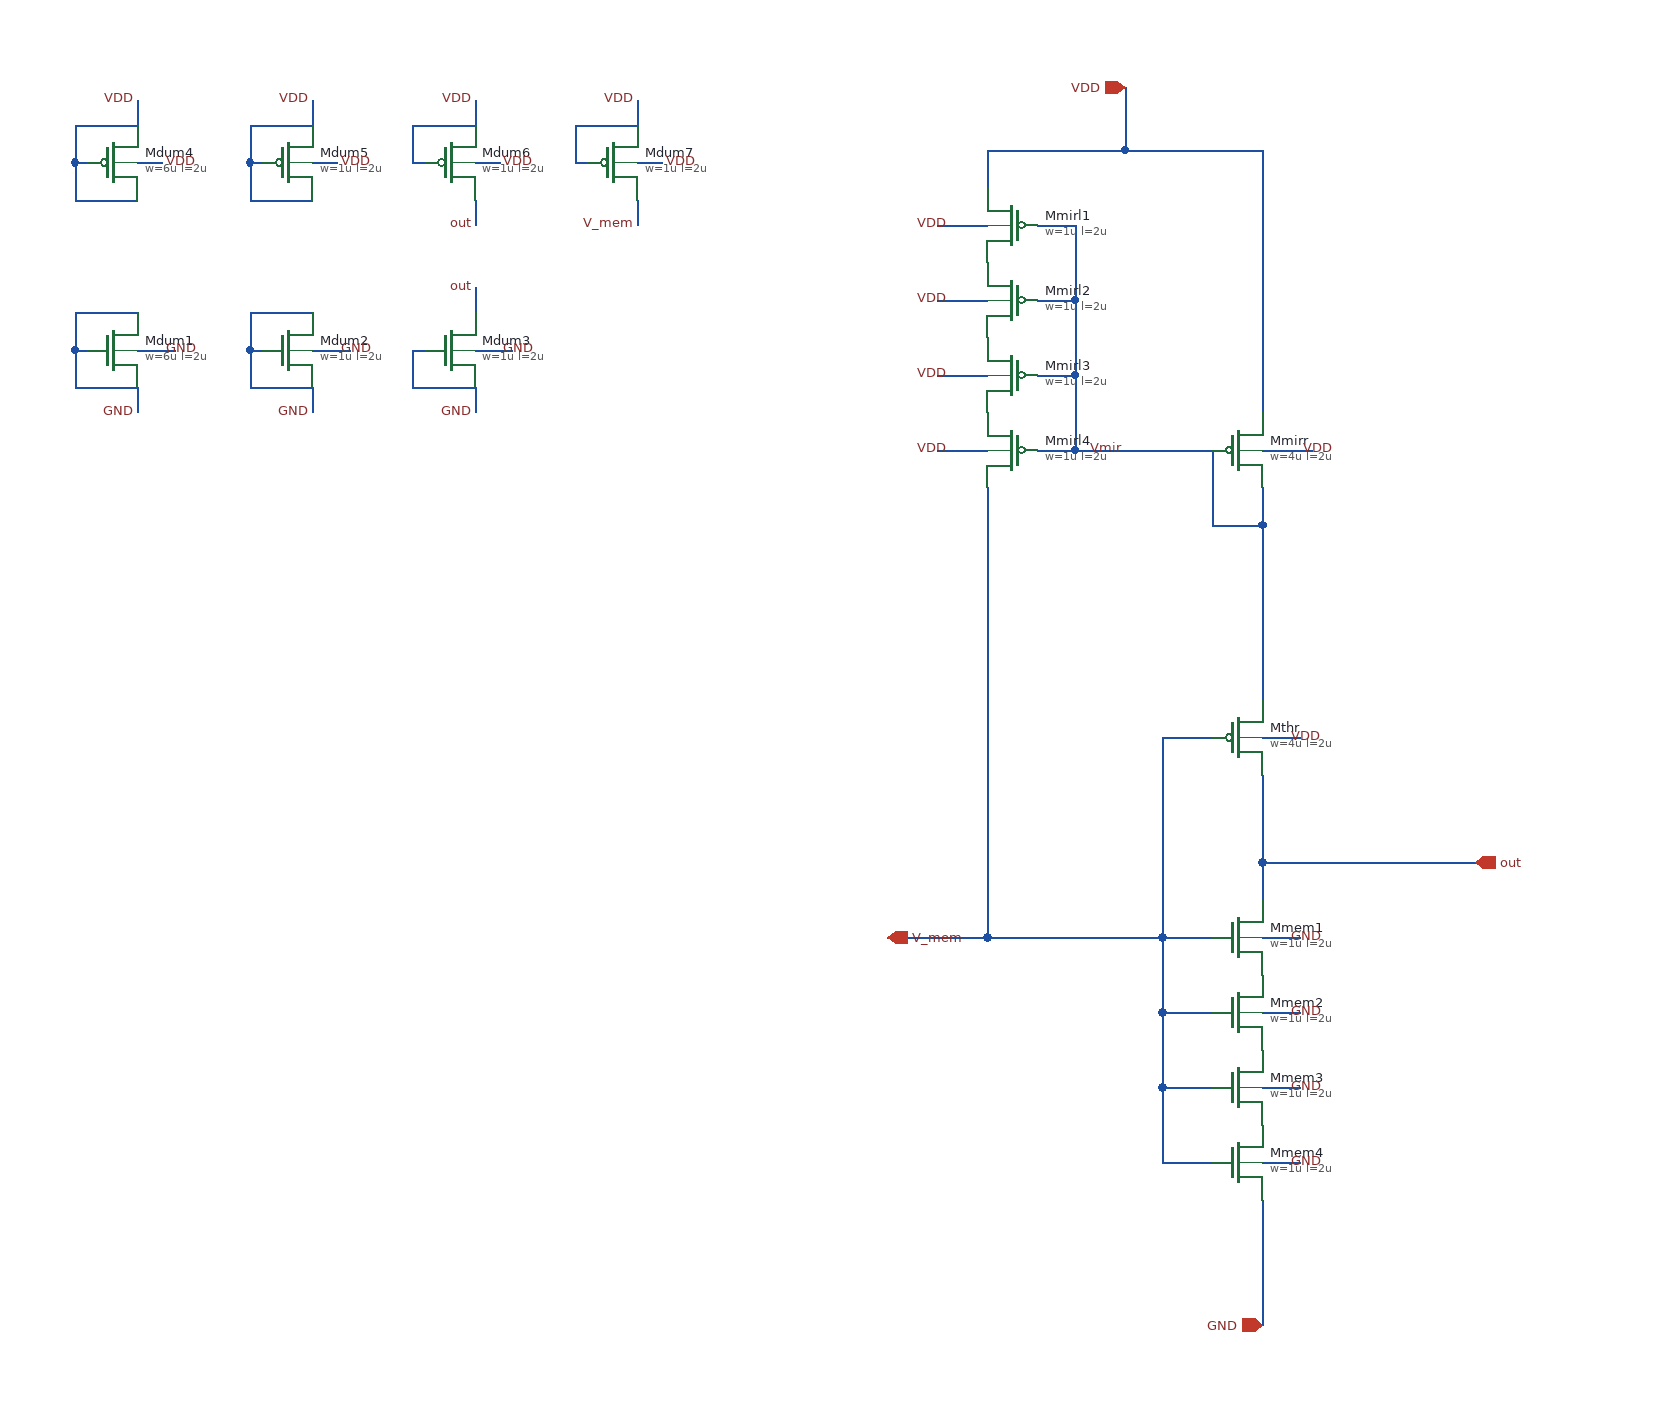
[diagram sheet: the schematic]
v {xschem version=3.4.8RC file_version=1.3}
G {}
K {}
V {}
S {}
F {}
E {}
N -1470 -1430 -1470 -1400 {lab=out}
N -1550 -1370 -1510 -1370 {lab=V_mem}
N -1470 -1500 -1470 -1430 {lab=out}
N -1550 -1530 -1510 -1530 {lab=V_mem}
N -1550 -1530 -1550 -1370 {lab=V_mem}
N -1510 -1760 -1510 -1700 {lab=Vmir}
N -1510 -1700 -1470 -1700 {lab=Vmir}
N -1470 -1730 -1470 -1700 {lab=Vmir}
N -1620 -1760 -1510 -1760 {lab=Vmir}
N -1470 -1430 -1300 -1430 {lab=out}
N -1580 -2050 -1580 -2000 {lab=VDD}
N -1580 -2000 -1470 -2000 {lab=VDD}
N -1690 -1730 -1690 -1370 {lab=V_mem}
N -1470 -1700 -1470 -1560 {lab=Vmir}
N -1470 -1370 -1440 -1370 {lab=psub}
N -1470 -1160 -1470 -1060 {lab=GND}
N -1470 -1530 -1440 -1530 {lab=VDD}
N -1690 -1370 -1550 -1370 {lab=V_mem}
N -1730 -1760 -1690 -1760 {lab=VDD}
N -1730 -1820 -1690 -1820 {lab=VDD}
N -1730 -1880 -1690 -1880 {lab=VDD}
N -1730 -1940 -1690 -1940 {lab=VDD}
N -1620 -1820 -1620 -1760 {lab=Vmir}
N -1650 -1760 -1620 -1760 {lab=Vmir}
N -1650 -1820 -1620 -1820 {lab=Vmir}
N -1620 -1880 -1620 -1820 {lab=Vmir}
N -1650 -1880 -1620 -1880 {lab=Vmir}
N -1620 -1940 -1620 -1880 {lab=Vmir}
N -1650 -1940 -1620 -1940 {lab=Vmir}
N -1690 -2000 -1690 -1970 {lab=VDD}
N -1470 -1760 -1430 -1760 {lab=VDD}
N -1470 -2000 -1470 -1790 {lab=VDD}
N -1470 -1310 -1440 -1310 {lab=psub}
N -1470 -1250 -1440 -1250 {lab=psub}
N -1470 -1190 -1440 -1190 {lab=psub}
N -1550 -1370 -1550 -1310 {lab=V_mem}
N -1550 -1310 -1510 -1310 {lab=V_mem}
N -1550 -1310 -1550 -1250 {lab=V_mem}
N -1550 -1250 -1510 -1250 {lab=V_mem}
N -1550 -1250 -1550 -1190 {lab=V_mem}
N -1550 -1190 -1510 -1190 {lab=V_mem}
N -1690 -2000 -1580 -2000 {lab=VDD}
N -1770 -1370 -1690 -1370 {lab=V_mem}
N -2370 -1840 -2340 -1840 {lab=GND}
N -2420 -1840 -2410 -1840 {lab=GND}
N -2420 -1840 -2420 -1810 {lab=GND}
N -2420 -1810 -2370 -1810 {lab=GND}
N -2420 -1870 -2420 -1840 {lab=GND}
N -2420 -1870 -2370 -1870 {lab=GND}
N -2230 -1840 -2200 -1840 {lab=GND}
N -2280 -1840 -2270 -1840 {lab=GND}
N -2280 -1840 -2280 -1810 {lab=GND}
N -2280 -1810 -2230 -1810 {lab=GND}
N -2280 -1870 -2280 -1840 {lab=GND}
N -2280 -1870 -2230 -1870 {lab=GND}
N -2100 -1840 -2070 -1840 {lab=GND}
N -2150 -1840 -2140 -1840 {lab=GND}
N -2150 -1840 -2150 -1810 {lab=GND}
N -2150 -1810 -2100 -1810 {lab=GND}
N -2370 -1810 -2370 -1790 {lab=GND}
N -2230 -1810 -2230 -1790 {lab=GND}
N -2100 -1810 -2100 -1790 {lab=GND}
N -2100 -1890 -2100 -1870 {lab=out}
N -2370 -1990 -2350 -1990 {lab=VDD}
N -2370 -2040 -2370 -2020 {lab=VDD}
N -2420 -1990 -2410 -1990 {lab=VDD}
N -2420 -1990 -2420 -1960 {lab=VDD}
N -2420 -1960 -2370 -1960 {lab=VDD}
N -2420 -2020 -2420 -1990 {lab=VDD}
N -2420 -2020 -2370 -2020 {lab=VDD}
N -2230 -1990 -2210 -1990 {lab=VDD}
N -2230 -2040 -2230 -2020 {lab=VDD}
N -2280 -1990 -2270 -1990 {lab=VDD}
N -2280 -1990 -2280 -1960 {lab=VDD}
N -2280 -1960 -2230 -1960 {lab=VDD}
N -2280 -2020 -2280 -1990 {lab=VDD}
N -2280 -2020 -2230 -2020 {lab=VDD}
N -2100 -1990 -2080 -1990 {lab=VDD}
N -2100 -2040 -2100 -2020 {lab=VDD}
N -2150 -1990 -2140 -1990 {lab=VDD}
N -2150 -2020 -2150 -1990 {lab=VDD}
N -2150 -2020 -2100 -2020 {lab=VDD}
N -2100 -1960 -2100 -1940 {lab=out}
N -1970 -1990 -1950 -1990 {lab=VDD}
N -1970 -2040 -1970 -2020 {lab=VDD}
N -2020 -1990 -2010 -1990 {lab=VDD}
N -2020 -2020 -2020 -1990 {lab=VDD}
N -2020 -2020 -1970 -2020 {lab=VDD}
N -1970 -1960 -1970 -1940 {lab=V_mem}
C {sg13g2_pr/sg13_hv_pmos.sym} -1490 -1760 0 0 {name=Mmirr
l=2u
w=4u
ng=4
m=1
model=sg13_hv_pmos
spiceprefix=X
}
C {sg13g2_pr/sg13_hv_pmos.sym} -1670 -1760 0 1 {name=Mmirl4
l=2u
w=1u
ng=1
m=1
model=sg13_hv_pmos
spiceprefix=X
}
C {sg13g2_pr/sg13_hv_pmos.sym} -1490 -1530 0 0 {name=Mthr
l=2u
w=4u
ng=4
m=1
model=sg13_hv_pmos
spiceprefix=X
}
C {opin.sym} -1300 -1430 0 0 {name=p1 lab=out}
C {iopin.sym} -1770 -1370 0 1 {name=p2 lab=V_mem
}
C {iopin.sym} -1580 -2050 0 0 {name=p3 lab=VDD}
C {iopin.sym} -1470 -1060 0 0 {name=p5 lab=GND}
C {sg13g2_pr/sg13_hv_nmos.sym} -1490 -1370 0 0 {name=Mmem1
l=2u
w=1u
ng=1
m=2
model=sg13_hv_nmos
spiceprefix=X
}
C {lab_wire.sym} -1450 -1370 0 1 {name=p4 sig_type=std_logic lab=GND}
C {lab_wire.sym} -1580 -1760 0 0 {name=p6 sig_type=std_logic lab=Vmir}
C {lab_wire.sym} -1450 -1530 0 1 {name=p7 sig_type=std_logic lab=VDD}
C {lab_wire.sym} -1720 -1760 0 0 {name=p9 sig_type=std_logic lab=VDD}
C {sg13g2_pr/sg13_hv_pmos.sym} -1670 -1820 0 1 {name=Mmirl3
l=2u
w=1u
ng=1
m=1
model=sg13_hv_pmos
spiceprefix=X
}
C {lab_wire.sym} -1720 -1820 0 0 {name=p10 sig_type=std_logic lab=VDD}
C {sg13g2_pr/sg13_hv_pmos.sym} -1670 -1880 0 1 {name=Mmirl2
l=2u
w=1u
ng=1
m=1
model=sg13_hv_pmos
spiceprefix=X
}
C {lab_wire.sym} -1720 -1880 0 0 {name=p11 sig_type=std_logic lab=VDD}
C {sg13g2_pr/sg13_hv_pmos.sym} -1670 -1940 0 1 {name=Mmirl1
l=2u
w=1u
ng=1
m=1
model=sg13_hv_pmos
spiceprefix=X
}
C {lab_wire.sym} -1720 -1940 0 0 {name=p12 sig_type=std_logic lab=VDD}
C {lab_wire.sym} -1440 -1760 0 1 {name=p13 sig_type=std_logic lab=VDD}
C {sg13g2_pr/sg13_hv_nmos.sym} -1490 -1310 0 0 {name=Mmem2
l=2u
w=1u
ng=1
m=2
model=sg13_hv_nmos
spiceprefix=X
}
C {lab_wire.sym} -1450 -1310 0 1 {name=p14 sig_type=std_logic lab=GND}
C {sg13g2_pr/sg13_hv_nmos.sym} -1490 -1250 0 0 {name=Mmem3
l=2u
w=1u
ng=1
m=2
model=sg13_hv_nmos
spiceprefix=X
}
C {lab_wire.sym} -1450 -1250 0 1 {name=p15 sig_type=std_logic lab=GND}
C {sg13g2_pr/sg13_hv_nmos.sym} -1490 -1190 0 0 {name=Mmem4
l=2u
w=1u
ng=1
m=2
model=sg13_hv_nmos
spiceprefix=X
}
C {lab_wire.sym} -1450 -1190 0 1 {name=p16 sig_type=std_logic lab=GND}
C {sg13g2_pr/sg13_hv_nmos.sym} -2390 -1840 0 0 {name=Mdum1
l=2u
w=6u
ng=6
m=2
model=sg13_hv_nmos
spiceprefix=X
}
C {lab_wire.sym} -2350 -1840 0 1 {name=p8 sig_type=std_logic lab=GND}
C {sg13g2_pr/sg13_hv_nmos.sym} -2250 -1840 0 0 {name=Mdum2
l=2u
w=1u
ng=1
m=2
model=sg13_hv_nmos
spiceprefix=X
}
C {lab_wire.sym} -2210 -1840 0 1 {name=p17 sig_type=std_logic lab=GND}
C {sg13g2_pr/sg13_hv_nmos.sym} -2120 -1840 0 0 {name=Mdum3
l=2u
w=1u
ng=1
m=2
model=sg13_hv_nmos
spiceprefix=X
}
C {lab_wire.sym} -2080 -1840 0 1 {name=p20 sig_type=std_logic lab=GND}
C {lab_wire.sym} -2370 -1790 0 0 {name=p22 sig_type=std_logic lab=GND
}
C {lab_wire.sym} -2230 -1790 0 0 {name=p18 sig_type=std_logic lab=GND
}
C {lab_wire.sym} -2100 -1790 0 0 {name=p19 sig_type=std_logic lab=GND
}
C {lab_wire.sym} -2100 -1890 0 0 {name=p21 sig_type=std_logic lab=out}
C {sg13g2_pr/sg13_hv_pmos.sym} -2390 -1990 0 0 {name=Mdum4
l=2u
w=6u
ng=6
m=2
model=sg13_hv_pmos
spiceprefix=X
}
C {lab_wire.sym} -2350 -1990 0 1 {name=p23 sig_type=std_logic lab=VDD}
C {lab_wire.sym} -2370 -2040 0 0 {name=p24 sig_type=std_logic lab=VDD}
C {sg13g2_pr/sg13_hv_pmos.sym} -2250 -1990 0 0 {name=Mdum5
l=2u
w=1u
ng=1
m=3
model=sg13_hv_pmos
spiceprefix=X
}
C {lab_wire.sym} -2210 -1990 0 1 {name=p25 sig_type=std_logic lab=VDD}
C {lab_wire.sym} -2230 -2040 0 0 {name=p26 sig_type=std_logic lab=VDD}
C {sg13g2_pr/sg13_hv_pmos.sym} -2120 -1990 0 0 {name=Mdum6
l=2u
w=1u
ng=1
m=2
model=sg13_hv_pmos
spiceprefix=X
}
C {lab_wire.sym} -2080 -1990 0 1 {name=p27 sig_type=std_logic lab=VDD}
C {lab_wire.sym} -2100 -2040 0 0 {name=p28 sig_type=std_logic lab=VDD}
C {lab_wire.sym} -2100 -1940 0 0 {name=p29 sig_type=std_logic lab=out}
C {sg13g2_pr/sg13_hv_pmos.sym} -1990 -1990 0 0 {name=Mdum7
l=2u
w=1u
ng=1
m=1
model=sg13_hv_pmos
spiceprefix=X
}
C {lab_wire.sym} -1950 -1990 0 1 {name=p30 sig_type=std_logic lab=VDD}
C {lab_wire.sym} -1970 -2040 0 0 {name=p31 sig_type=std_logic lab=VDD}
C {lab_wire.sym} -1970 -1940 0 0 {name=p32 sig_type=std_logic lab=V_mem}
